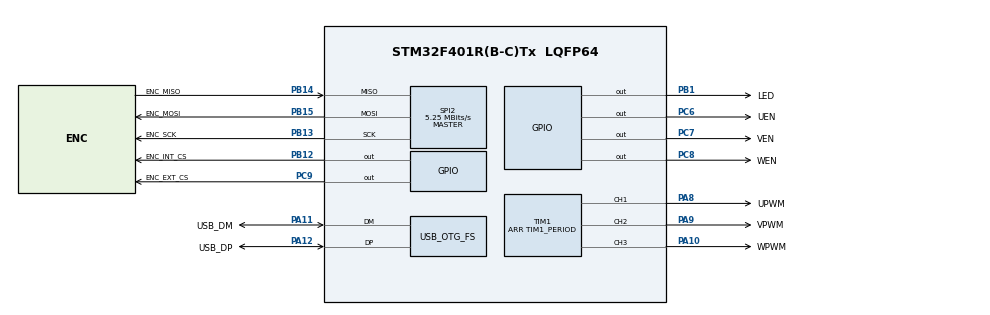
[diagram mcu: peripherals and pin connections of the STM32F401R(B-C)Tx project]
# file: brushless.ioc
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Mcu.Family=STM32F4
Mcu.Name=STM32F401R(B-C)Tx
Mcu.Package=LQFP64
NVIC.OTG_FS_IRQn=true\:2\:0\:true\:false\:true\:false\:true
NVIC.PriorityGroup=NVIC_PRIORITYGROUP_4
NVIC.SPI2_IRQn=true\:1\:0\:true\:false\:true\:true\:true
NVIC.TIM2_IRQn=true\:0\:0\:false\:false\:true\:true\:true
NVIC.TIM3_IRQn=true\:0\:0\:false\:false\:true\:true\:true
NVIC.TIM5_IRQn=true\:0\:0\:false\:false\:true\:true\:true
PA10.GPIO_Label=WPWM
PA10.Signal=S_TIM1_CH3
PA11.GPIO_Label=USB_DM
PA11.Mode=Device_Only
PA11.Signal=USB_OTG_FS_DM
PA12.GPIO_Label=USB_DP
PA12.Mode=Device_Only
PA12.Signal=USB_OTG_FS_DP
PA13.Mode=JTAG_4_pins
PA13.Signal=SYS_JTMS-SWDIO
PA14.Mode=JTAG_4_pins
PA14.Signal=SYS_JTCK-SWCLK
PA15.Mode=JTAG_4_pins
PA15.Signal=SYS_JTDI
PA8.GPIO_Label=UPWM
PA8.Signal=S_TIM1_CH1
PA9.GPIO_Label=VPWM
PA9.Signal=S_TIM1_CH2
PB1.GPIO_Label=LED
PB1.Signal=GPIO_Output
PB12.GPIO_Label=ENC_INT_CS
PB12.GPIO_Speed=GPIO_SPEED_FREQ_VERY_HIGH
PB12.PinState=GPIO_PIN_SET
PB12.Signal=GPIO_Output
PB13.GPIO_Label=ENC_SCK
PB13.Mode=Full_Duplex_Master
PB13.Signal=SPI2_SCK
PB14.GPIO_Label=ENC_MISO
PB14.Mode=Full_Duplex_Master
PB14.Signal=SPI2_MISO
PB15.GPIO_Label=ENC_MOSI
PB15.Mode=Full_Duplex_Master
PB15.Signal=SPI2_MOSI
PB3.Mode=JTAG_4_pins
PB3.Signal=SYS_JTDO-SWO
PC14-OSC32_IN.Mode=LSE-External-Oscillator
PC14-OSC32_IN.Signal=RCC_OSC32_IN
PC15-OSC32_OUT.Mode=LSE-External-Oscillator
PC15-OSC32_OUT.Signal=RCC_OSC32_OUT
PC6.GPIO_Label=UEN
PC6.Signal=GPIO_Output
PC7.GPIO_Label=VEN
PC7.Signal=GPIO_Output
PC8.GPIO_Label=WEN
PC8.Signal=GPIO_Output
PC9.GPIO_Label=ENC_EXT_CS
PC9.GPIO_Speed=GPIO_SPEED_FREQ_VERY_HIGH
PC9.PinState=GPIO_PIN_SET
PC9.Signal=GPIO_Output
PH0\ -\ OSC_IN.Mode=HSE-External-Oscillator
PH0\ -\ OSC_IN.Signal=RCC_OSC_IN
PH1\ -\ OSC_OUT.Mode=HSE-External-Oscillator
PH1\ -\ OSC_OUT.Signal=RCC_OSC_OUT
ProjectManager.HeapSize=0x200
ProjectManager.StackSize=0x400
ProjectManager.TargetToolchain=Makefile
RCC.48MHZClocksFreq_Value=48000000
RCC.AHBFreq_Value=84000000
RCC.APB1CLKDivider=RCC_HCLK_DIV2
RCC.APB1Freq_Value=42000000
RCC.APB1TimFreq_Value=84000000
RCC.APB2Freq_Value=84000000
RCC.APB2TimFreq_Value=84000000
RCC.CortexFreq_Value=84000000
RCC.HCLKFreq_Value=84000000
RCC.HSE_VALUE=8000000
RCC.HSI_VALUE=16000000
RCC.PLLM=4
RCC.PLLN=168
RCC.PLLP=RCC_PLLP_DIV4
RCC.PLLQ=7
RCC.RCC_RTC_Clock_Source=RCC_RTCCLKSOURCE_LSE
RCC.RCC_RTC_Clock_SourceVirtual=RCC_RTCCLKSOURCE_LSE
RCC.SYSCLKFreq_VALUE=84000000
RCC.SYSCLKSource=RCC_SYSCLKSOURCE_PLLCLK
RCC.VCOOutputFreq_Value=336000000
SH.S_TIM1_CH1.0=TIM1_CH1,PWM Generation1 CH1
SH.S_TIM1_CH2.0=TIM1_CH2,PWM Generation2 CH2
SH.S_TIM1_CH3.0=TIM1_CH3,PWM Generation3 CH3
SPI2.BaudRatePrescaler=SPI_BAUDRATEPRESCALER_8
SPI2.CLKPhase=SPI_PHASE_2EDGE
SPI2.CalculateBaudRate=5.25 MBits/s
SPI2.Direction=SPI_DIRECTION_2LINES
SPI2.Mode=SPI_MODE_MASTER
SPI2.VirtualType=VM_MASTER
TIM1.Channel-PWM\ Generation1\ CH1=TIM_CHANNEL_1
TIM1.Channel-PWM\ Generation2\ CH2=TIM_CHANNEL_2
TIM1.Channel-PWM\ Generation3\ CH3=TIM_CHANNEL_3
TIM1.CounterMode=TIM_COUNTERMODE_CENTERALIGNED3
TIM1.Period=TIM1_PERIOD
TIM1.Prescaler=TIM1_PRESCALAR
TIM1.TIM_MasterOutputTrigger=TIM_TRGO_RESET
TIM1.TIM_MasterSlaveMode=TIM_MASTERSLAVEMODE_DISABLE
TIM2.Period=TIM2_PERIOD
TIM2.Prescaler=TIM2_PRESCALAR
TIM2.TIM_MasterOutputTrigger=TIM_TRGO_RESET
TIM3.Channel-Output\ Compare1\ No\ Output=TIM_CHANNEL_1
TIM3.OCMode_1=TIM_OCMODE_TIMING
TIM3.Period=TIM3_PERIOD
TIM3.Prescaler=TIM3_PRESCALAR
TIM3.Pulse-Output\ Compare1\ No\ Output=ENC_SPI_DELAY
TIM3.TIM_MasterOutputTrigger=TIM_TRGO_RESET
TIM4.Period=TIM4_PERIOD
TIM4.Prescaler=TIM4_PRESCALAR
TIM4.TIM_MasterOutputTrigger=TIM_TRGO_UPDATE
TIM4.TIM_MasterSlaveMode=TIM_MASTERSLAVEMODE_ENABLE
TIM5.Channel-Output\ Compare1\ No\ Output=TIM_CHANNEL_1
TIM5.Period=TIM5_PERIOD
TIM5.Prescaler=TIM5_PRESCALAR
TIM5.Pulse-Output\ Compare1\ No\ Output=COMP_DELAY
USB_DEVICE.CLASS_NAME_FS=CDC
USB_DEVICE.MANUFACTURER_STRING=OpenHandicap
USB_DEVICE.PID_CDC_FS=0x4567
USB_DEVICE.PRODUCT_STRING_CDC_FS=Brushless Driver
USB_DEVICE.VID=0xF123
USB_DEVICE.VirtualMode=Cdc
USB_DEVICE.VirtualModeFS=Cdc_FS
USB_OTG_FS.VirtualMode=Device_Only
VP_TIM1_VS_ClockSourceINT.Mode=Internal
VP_TIM1_VS_ClockSourceITR.Mode=TriggerSource_ITR3
VP_TIM1_VS_ControllerModeReset.Mode=Reset Mode
VP_TIM2_VS_ClockSourceINT.Mode=Internal
VP_TIM2_VS_ClockSourceITR.Mode=TriggerSource_ITR3
VP_TIM2_VS_ControllerModeReset.Mode=Reset Mode
VP_TIM3_VS_ClockSourceINT.Mode=Internal
VP_TIM3_VS_ClockSourceITR.Mode=TriggerSource_ITR3
VP_TIM3_VS_ControllerModeReset.Mode=Reset Mode
VP_TIM3_VS_no_output1.Mode=Output Compare1 No Output
VP_TIM4_VS_ClockSourceINT.Mode=Internal
VP_TIM5_VS_ClockSourceINT.Mode=Internal
VP_TIM5_VS_no_output1.Mode=Output Compare1 No Output
VP_USB_DEVICE_VS_USB_DEVICE_CDC_FS.Mode=CDC_FS
board=custom

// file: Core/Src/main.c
/* USER CODE BEGIN Header */
/**
  ******************************************************************************
  * @file           : main.c
  * @brief          : Main program body
  ******************************************************************************
  * @attention
  *
  * <h2><center>&copy; Copyright (c) 2019 STMicroelectronics.
  * All rights reserved.</center></h2>
  * <h2><center>&copy; Copyright (c) 2019 Adrien Boussicault (USER CODE).
  * </center></h2>
  *
  * This software component is licensed by ST under BSD 3-Clause license,
  * the "License"; You may not use this file except in compliance with the
  * License. You may obtain a copy of the License at:
  *                        opensource.org/licenses/BSD-3-Clause
  *
  ******************************************************************************
  */
/* USER CODE END Header */

#include "main.h"
#include "usb_device.h"

/* USER CODE BEGIN Includes */
#include <terminal.h>
#include "debug.h"
#include "usbd_cdc_if.h"
#include <time.h>
#include <encoder.h>
#include <system.h>
#include <errors.h>
#include <frequence_definitions.h>

#define TIM1_PERIOD PWM_PERIOD
#define TIM2_PERIOD 2*PWM_PERIOD
#define TIM3_PERIOD 2*PWM_PERIOD*ENCODER_PERIOD
#define TIM4_PERIOD 4
#define TIM5_PERIOD 4294967295
#define TIM1_PRESCALAR 0
#define TIM2_PRESCALAR 0
#define TIM3_PRESCALAR 0
#define TIM4_PRESCALAR 0
#define TIM5_PRESCALAR 150 //5000
#define COMP_DELAY 1
/* USER CODE END Includes */

SPI_HandleTypeDef hspi2;

TIM_HandleTypeDef htim1;
TIM_HandleTypeDef htim2;
TIM_HandleTypeDef htim3;
TIM_HandleTypeDef htim4;
TIM_HandleTypeDef htim5;

void SystemClock_Config(void);
static void MX_GPIO_Init(void);
static void MX_SPI2_Init(void);
static void MX_TIM1_Init(void);
static void MX_TIM2_Init(void);
static void MX_TIM3_Init(void);
static void MX_TIM4_Init(void);
static void MX_TIM5_Init(void);

/* USER CODE BEGIN 0 */
TERMINAL_COMMAND(version, "firmware version")
{
  terminal_println(FIRMWARE_VERSION);
}

TERMINAL_COMMAND(led, "Set led")
{
  if(argc == 0){
    HAL_GPIO_TogglePin(LED_GPIO_Port, LED_Pin);
  }else if(argc == 1){
    if( atoi(argv[0])==1 ){
      HAL_GPIO_WritePin(LED_GPIO_Port, LED_Pin, GPIO_PIN_SET);
    }else{
      HAL_GPIO_WritePin(LED_GPIO_Port, LED_Pin, GPIO_PIN_RESET);
    }
  }else{
    terminal_println("Usage: led [1|0]");
  }
}

TERMINAL_COMMAND(test_us, "test micro oscillation on LED.")
{
  while(1){
    delay_us(1);
    HAL_GPIO_TogglePin(LED_GPIO_Port, LED_Pin);
  }
}

#ifdef DEBUG
TERMINAL_COMMAND(test_ms, "test milli oscillation on LED.")
{
  while(1){
    DELAY_MS(1);
    HAL_GPIO_TogglePin(LED_GPIO_Port, LED_Pin);
  }
}
#endif

TERMINAL_COMMAND(test_ns, "test milli oscillation on LED.")
{
  while(1){
    DELAY_AT_LEAST_NS(350);
    HAL_GPIO_TogglePin(LED_GPIO_Port, LED_Pin);
  }
}

void HAL_SPI_ErrorCallback(SPI_HandleTypeDef* hspi){
  if(hspi == &hspi2){
    encoder_error_spi_call_back();
  }
}

void HAL_SPI_TxRxCpltCallback(SPI_HandleTypeDef* hspi){
  if(hspi == &hspi2){
    encoder_spi_call_back();
  }
}

TERMINAL_PARAMETER_BOOL(st, "decl", false);

void start_and_synchronize_timers(){
  // We start timer 1, 2 and 4
  if( HAL_TIM_Base_Start(&htim1) != HAL_OK ){
    raise_error(ERROR_TIMER_INIT_AT_LINE, __LINE__);
  }
  if( HAL_TIM_Base_Start(&htim2) != HAL_OK ){
    raise_error(ERROR_TIMER_INIT_AT_LINE, __LINE__);
  }
  if( HAL_TIM_Base_Start(&htim3) != HAL_OK ){
    raise_error(ERROR_TIMER_INIT_AT_LINE, __LINE__);
  }

  //
  // Now, we will synchronize all timer by using the timer 4
  // Timer 4 is configured to send a trigger output (whose name is ITR3)
  // at each update.
  // Timer 1, 2, 3 are in slave mode, configured in reset mode and are waiting
  // for an input signal from TIM 4 (by using ITR3) to be reseted.
  //
  if( HAL_TIM_Base_Start(&htim4) != HAL_OK ){
     raise_error(ERROR_TIMER_INIT_AT_LINE, __LINE__);
  }
  delay_us(1); // We wait a little, to give time to TIM4 to be updated() (and
  //DELAY_MS(10000); // We wait a little, to give time to TIM4 to be updated() (and
                // ant trigger an output signal.
  if( HAL_TIM_Base_Stop(&htim4) != HAL_OK ){
    raise_error(ERROR_TIMER_INIT_AT_LINE, __LINE__);
  }

  // We can now start Output compare and interuption for timer 1, 2 and 3.
  if( HAL_TIM_OC_Start(&htim3, TIM_CHANNEL_1) != HAL_OK){
    raise_error(ERROR_TIMER_INIT_AT_LINE, __LINE__);
  };
  if( HAL_TIM_OC_Start_IT(&htim3, TIM_CHANNEL_1) != HAL_OK){
    raise_error(ERROR_TIMER_INIT_AT_LINE, __LINE__);
  };

  if( HAL_TIM_Base_Start_IT(&htim3) != HAL_OK ){
    raise_error(ERROR_TIMER_INIT_AT_LINE, __LINE__);
  }
  if( HAL_TIM_Base_Start_IT(&htim2) != HAL_OK ){
    raise_error(ERROR_TIMER_INIT_AT_LINE, __LINE__);
  };
  if( HAL_TIM_Base_Start_IT(&htim3) != HAL_OK ){
    raise_error(ERROR_TIMER_INIT_AT_LINE, __LINE__);
  }

    if( HAL_TIM_Base_Start(&htim5) != HAL_OK ){
      raise_error(ERROR_TIMER_INIT_AT_LINE, __LINE__);
    }
    if( HAL_TIM_OC_Start(&htim5, TIM_CHANNEL_1) != HAL_OK){
      raise_error(ERROR_TIMER_INIT_AT_LINE, __LINE__);
    };
    if( HAL_TIM_OC_Start_IT(&htim5, TIM_CHANNEL_1) != HAL_OK){
      raise_error(ERROR_TIMER_INIT_AT_LINE, __LINE__);
    };
}
/* USER CODE END 0 */

int main(void)
{

  /* MCU Configuration--------------------------------------------------------*/

  /* Reset of all peripherals, Initializes the Flash interface and the Systick. */
  HAL_Init();

  /* Configure the system clock */
  SystemClock_Config();

  /* Initialize all configured peripherals */
  MX_GPIO_Init();
  MX_SPI2_Init();
  MX_TIM1_Init();
  MX_TIM2_Init();
  MX_TIM3_Init();
  MX_TIM4_Init();
  MX_TIM5_Init();
  MX_USB_DEVICE_Init();
  /* USER CODE BEGIN 2 */

  get_serial()->init();
  terminal_init(get_serial());

  system_init();
  encoder_init(&hspi2, ENC_INT_CS_GPIO_Port,ENC_INT_CS_Pin);

  start_and_synchronize_timers();
  encoder_start();
  /* USER CODE END 2 */

  /* Infinite loop */
  /* USER CODE BEGIN WHILE */
  while (1)
  {
    system_tick();
#if 0
    COUNTDOWN(100){
      FREQ(frequence, 8);
      if( st ){
        HAL_GPIO_TogglePin(LED_GPIO_Port, LED_Pin);
        // HAL_GPIO_WritePin(LED_GPIO_Port, LED_Pin, GPIO_PIN_SET);
        start_read_encoder_position();
      }
      WATCHJ(true, 2000, "%.3f Khz", frequence/1000);
    }
#endif
    encoder_tick();
    get_serial()->tick();
    terminal_tick();

    /* USER CODE END WHILE */

  }
}

void SystemClock_Config(void)
{
  RCC_OscInitTypeDef RCC_OscInitStruct = {0};
  RCC_ClkInitTypeDef RCC_ClkInitStruct = {0};

  /** Configure the main internal regulator output voltage
  */
  __HAL_RCC_PWR_CLK_ENABLE();
  __HAL_PWR_VOLTAGESCALING_CONFIG(PWR_REGULATOR_VOLTAGE_SCALE2);
  /** Initializes the CPU, AHB and APB busses clocks
  */
  RCC_OscInitStruct.OscillatorType = RCC_OSCILLATORTYPE_HSE;
  RCC_OscInitStruct.HSEState = RCC_HSE_ON;
  RCC_OscInitStruct.PLL.PLLState = RCC_PLL_ON;
  RCC_OscInitStruct.PLL.PLLSource = RCC_PLLSOURCE_HSE;
  RCC_OscInitStruct.PLL.PLLM = CLK_PLLM;
  RCC_OscInitStruct.PLL.PLLN = CLK_PLLN;
  RCC_OscInitStruct.PLL.PLLP = RCC_PLLP_DIV4;
  _Static_assert( CLK_PLLP == RCC_PLLP_DIV4, "");
  RCC_OscInitStruct.PLL.PLLQ = 7;
  if (HAL_RCC_OscConfig(&RCC_OscInitStruct) != HAL_OK)
  {
    main_error_handler(__LINE__);
  }
  /** Initializes the CPU, AHB and APB busses clocks
  */
  RCC_ClkInitStruct.ClockType = RCC_CLOCKTYPE_HCLK|RCC_CLOCKTYPE_SYSCLK
                              |RCC_CLOCKTYPE_PCLK1|RCC_CLOCKTYPE_PCLK2;
  RCC_ClkInitStruct.SYSCLKSource = RCC_SYSCLKSOURCE_PLLCLK;
  RCC_ClkInitStruct.AHBCLKDivider = RCC_SYSCLK_DIV1;
  RCC_ClkInitStruct.APB1CLKDivider = RCC_HCLK_DIV2;
  RCC_ClkInitStruct.APB2CLKDivider = RCC_HCLK_DIV1;

  if (HAL_RCC_ClockConfig(&RCC_ClkInitStruct, FLASH_LATENCY_2) != HAL_OK)
  {
    main_error_handler(__LINE__);
  }
}

static void MX_SPI2_Init(void)
{

  /* SPI2 parameter configuration*/
  hspi2.Instance = SPI2;
  hspi2.Init.Mode = SPI_MODE_MASTER;
  hspi2.Init.Direction = SPI_DIRECTION_2LINES;
  hspi2.Init.DataSize = SPI_DATASIZE_8BIT;
  hspi2.Init.CLKPolarity = SPI_POLARITY_LOW;
  hspi2.Init.CLKPhase = SPI_PHASE_2EDGE;
  hspi2.Init.NSS = SPI_NSS_SOFT;
  hspi2.Init.BaudRatePrescaler = SPI_BAUDRATEPRESCALER_8;
  hspi2.Init.FirstBit = SPI_FIRSTBIT_MSB;
  hspi2.Init.TIMode = SPI_TIMODE_DISABLE;
  hspi2.Init.CRCCalculation = SPI_CRCCALCULATION_DISABLE;
  hspi2.Init.CRCPolynomial = 10;
  if (HAL_SPI_Init(&hspi2) != HAL_OK)
  {
    main_error_handler(__LINE__);
  }

}

static void MX_TIM1_Init(void)
{

  TIM_ClockConfigTypeDef sClockSourceConfig = {0};
  TIM_SlaveConfigTypeDef sSlaveConfig = {0};
  TIM_MasterConfigTypeDef sMasterConfig = {0};
  TIM_OC_InitTypeDef sConfigOC = {0};
  TIM_BreakDeadTimeConfigTypeDef sBreakDeadTimeConfig = {0};

  htim1.Instance = TIM1;
  htim1.Init.Prescaler = TIM1_PRESCALAR;
  htim1.Init.CounterMode = TIM_COUNTERMODE_CENTERALIGNED3;
  htim1.Init.Period = TIM1_PERIOD;
  htim1.Init.ClockDivision = TIM_CLOCKDIVISION_DIV1;
  htim1.Init.RepetitionCounter = 0;
  htim1.Init.AutoReloadPreload = TIM_AUTORELOAD_PRELOAD_DISABLE;
  if (HAL_TIM_Base_Init(&htim1) != HAL_OK)
  {
    main_error_handler(__LINE__);
  }
  sClockSourceConfig.ClockSource = TIM_CLOCKSOURCE_INTERNAL;
  if (HAL_TIM_ConfigClockSource(&htim1, &sClockSourceConfig) != HAL_OK)
  {
    main_error_handler(__LINE__);
  }
  if (HAL_TIM_PWM_Init(&htim1) != HAL_OK)
  {
    main_error_handler(__LINE__);
  }
  sSlaveConfig.SlaveMode = TIM_SLAVEMODE_RESET;
  sSlaveConfig.InputTrigger = TIM_TS_ITR3;
  if (HAL_TIM_SlaveConfigSynchro(&htim1, &sSlaveConfig) != HAL_OK)
  {
    main_error_handler(__LINE__);
  }
  sMasterConfig.MasterOutputTrigger = TIM_TRGO_RESET;
  sMasterConfig.MasterSlaveMode = TIM_MASTERSLAVEMODE_DISABLE;
  if (HAL_TIMEx_MasterConfigSynchronization(&htim1, &sMasterConfig) != HAL_OK)
  {
    main_error_handler(__LINE__);
  }
  sConfigOC.OCMode = TIM_OCMODE_PWM1;
  sConfigOC.Pulse = 0;
  sConfigOC.OCPolarity = TIM_OCPOLARITY_HIGH;
  sConfigOC.OCNPolarity = TIM_OCNPOLARITY_HIGH;
  sConfigOC.OCFastMode = TIM_OCFAST_DISABLE;
  sConfigOC.OCIdleState = TIM_OCIDLESTATE_RESET;
  sConfigOC.OCNIdleState = TIM_OCNIDLESTATE_RESET;
  if (HAL_TIM_PWM_ConfigChannel(&htim1, &sConfigOC, TIM_CHANNEL_1) != HAL_OK)
  {
    main_error_handler(__LINE__);
  }
  if (HAL_TIM_PWM_ConfigChannel(&htim1, &sConfigOC, TIM_CHANNEL_2) != HAL_OK)
  {
    main_error_handler(__LINE__);
  }
  if (HAL_TIM_PWM_ConfigChannel(&htim1, &sConfigOC, TIM_CHANNEL_3) != HAL_OK)
  {
    main_error_handler(__LINE__);
  }
  sBreakDeadTimeConfig.OffStateRunMode = TIM_OSSR_DISABLE;
  sBreakDeadTimeConfig.OffStateIDLEMode = TIM_OSSI_DISABLE;
  sBreakDeadTimeConfig.LockLevel = TIM_LOCKLEVEL_OFF;
  sBreakDeadTimeConfig.DeadTime = 0;
  sBreakDeadTimeConfig.BreakState = TIM_BREAK_DISABLE;
  sBreakDeadTimeConfig.BreakPolarity = TIM_BREAKPOLARITY_HIGH;
  sBreakDeadTimeConfig.AutomaticOutput = TIM_AUTOMATICOUTPUT_DISABLE;
  if (HAL_TIMEx_ConfigBreakDeadTime(&htim1, &sBreakDeadTimeConfig) != HAL_OK)
  {
    main_error_handler(__LINE__);
  }
  HAL_TIM_MspPostInit(&htim1);

}

static void MX_TIM2_Init(void)
{

  TIM_ClockConfigTypeDef sClockSourceConfig = {0};
  TIM_SlaveConfigTypeDef sSlaveConfig = {0};
  TIM_MasterConfigTypeDef sMasterConfig = {0};

  htim2.Instance = TIM2;
  htim2.Init.Prescaler = TIM2_PRESCALAR;
  htim2.Init.CounterMode = TIM_COUNTERMODE_UP;
  htim2.Init.Period = TIM2_PERIOD;
  htim2.Init.ClockDivision = TIM_CLOCKDIVISION_DIV1;
  htim2.Init.AutoReloadPreload = TIM_AUTORELOAD_PRELOAD_DISABLE;
  if (HAL_TIM_Base_Init(&htim2) != HAL_OK)
  {
    main_error_handler(__LINE__);
  }
  sClockSourceConfig.ClockSource = TIM_CLOCKSOURCE_INTERNAL;
  if (HAL_TIM_ConfigClockSource(&htim2, &sClockSourceConfig) != HAL_OK)
  {
    main_error_handler(__LINE__);
  }
  sSlaveConfig.SlaveMode = TIM_SLAVEMODE_RESET;
  sSlaveConfig.InputTrigger = TIM_TS_ITR3;
  if (HAL_TIM_SlaveConfigSynchro(&htim2, &sSlaveConfig) != HAL_OK)
  {
    main_error_handler(__LINE__);
  }
  sMasterConfig.MasterOutputTrigger = TIM_TRGO_RESET;
  sMasterConfig.MasterSlaveMode = TIM_MASTERSLAVEMODE_DISABLE;
  if (HAL_TIMEx_MasterConfigSynchronization(&htim2, &sMasterConfig) != HAL_OK)
  {
    main_error_handler(__LINE__);
  }

}

static void MX_TIM3_Init(void)
{

  TIM_ClockConfigTypeDef sClockSourceConfig = {0};
  TIM_SlaveConfigTypeDef sSlaveConfig = {0};
  TIM_MasterConfigTypeDef sMasterConfig = {0};
  TIM_OC_InitTypeDef sConfigOC = {0};

  htim3.Instance = TIM3;
  htim3.Init.Prescaler = TIM3_PRESCALAR;
  htim3.Init.CounterMode = TIM_COUNTERMODE_UP;
  htim3.Init.Period = TIM3_PERIOD;
  htim3.Init.ClockDivision = TIM_CLOCKDIVISION_DIV1;
  htim3.Init.AutoReloadPreload = TIM_AUTORELOAD_PRELOAD_DISABLE;
  if (HAL_TIM_Base_Init(&htim3) != HAL_OK)
  {
    main_error_handler(__LINE__);
  }
  sClockSourceConfig.ClockSource = TIM_CLOCKSOURCE_INTERNAL;
  if (HAL_TIM_ConfigClockSource(&htim3, &sClockSourceConfig) != HAL_OK)
  {
    main_error_handler(__LINE__);
  }
  if (HAL_TIM_OC_Init(&htim3) != HAL_OK)
  {
    main_error_handler(__LINE__);
  }
  sSlaveConfig.SlaveMode = TIM_SLAVEMODE_RESET;
  sSlaveConfig.InputTrigger = TIM_TS_ITR3;
  if (HAL_TIM_SlaveConfigSynchro(&htim3, &sSlaveConfig) != HAL_OK)
  {
    main_error_handler(__LINE__);
  }
  sMasterConfig.MasterOutputTrigger = TIM_TRGO_RESET;
  sMasterConfig.MasterSlaveMode = TIM_MASTERSLAVEMODE_DISABLE;
  if (HAL_TIMEx_MasterConfigSynchronization(&htim3, &sMasterConfig) != HAL_OK)
  {
    main_error_handler(__LINE__);
  }
  sConfigOC.OCMode = TIM_OCMODE_TIMING;
  sConfigOC.Pulse = ENC_SPI_DELAY;
  sConfigOC.OCPolarity = TIM_OCPOLARITY_HIGH;
  sConfigOC.OCFastMode = TIM_OCFAST_DISABLE;
  if (HAL_TIM_OC_ConfigChannel(&htim3, &sConfigOC, TIM_CHANNEL_1) != HAL_OK)
  {
    main_error_handler(__LINE__);
  }

}

static void MX_TIM4_Init(void)
{

  TIM_ClockConfigTypeDef sClockSourceConfig = {0};
  TIM_MasterConfigTypeDef sMasterConfig = {0};

  htim4.Instance = TIM4;
  htim4.Init.Prescaler = TIM4_PRESCALAR;
  htim4.Init.CounterMode = TIM_COUNTERMODE_UP;
  htim4.Init.Period = TIM4_PERIOD;
  htim4.Init.ClockDivision = TIM_CLOCKDIVISION_DIV1;
  htim4.Init.AutoReloadPreload = TIM_AUTORELOAD_PRELOAD_DISABLE;
  if (HAL_TIM_Base_Init(&htim4) != HAL_OK)
  {
    main_error_handler(__LINE__);
  }
  sClockSourceConfig.ClockSource = TIM_CLOCKSOURCE_INTERNAL;
  if (HAL_TIM_ConfigClockSource(&htim4, &sClockSourceConfig) != HAL_OK)
  {
    main_error_handler(__LINE__);
  }
  sMasterConfig.MasterOutputTrigger = TIM_TRGO_UPDATE;
  sMasterConfig.MasterSlaveMode = TIM_MASTERSLAVEMODE_ENABLE;
  if (HAL_TIMEx_MasterConfigSynchronization(&htim4, &sMasterConfig) != HAL_OK)
  {
    main_error_handler(__LINE__);
  }

}

static void MX_TIM5_Init(void)
{

  TIM_ClockConfigTypeDef sClockSourceConfig = {0};
  TIM_MasterConfigTypeDef sMasterConfig = {0};
  TIM_OC_InitTypeDef sConfigOC = {0};

  htim5.Instance = TIM5;
  htim5.Init.Prescaler = TIM5_PRESCALAR;
  htim5.Init.CounterMode = TIM_COUNTERMODE_UP;
  htim5.Init.Period = TIM5_PERIOD;
  htim5.Init.ClockDivision = TIM_CLOCKDIVISION_DIV1;
  htim5.Init.AutoReloadPreload = TIM_AUTORELOAD_PRELOAD_DISABLE;
  if (HAL_TIM_Base_Init(&htim5) != HAL_OK)
  {
    main_error_handler(__LINE__);
  }
  sClockSourceConfig.ClockSource = TIM_CLOCKSOURCE_INTERNAL;
  if (HAL_TIM_ConfigClockSource(&htim5, &sClockSourceConfig) != HAL_OK)
  {
    main_error_handler(__LINE__);
  }
  if (HAL_TIM_OC_Init(&htim5) != HAL_OK)
  {
    main_error_handler(__LINE__);
  }
  sMasterConfig.MasterOutputTrigger = TIM_TRGO_RESET;
  sMasterConfig.MasterSlaveMode = TIM_MASTERSLAVEMODE_DISABLE;
  if (HAL_TIMEx_MasterConfigSynchronization(&htim5, &sMasterConfig) != HAL_OK)
  {
    main_error_handler(__LINE__);
  }
  sConfigOC.OCMode = TIM_OCMODE_TIMING;
  sConfigOC.Pulse = COMP_DELAY;
  sConfigOC.OCPolarity = TIM_OCPOLARITY_HIGH;
  sConfigOC.OCFastMode = TIM_OCFAST_DISABLE;
  if (HAL_TIM_OC_ConfigChannel(&htim5, &sConfigOC, TIM_CHANNEL_1) != HAL_OK)
  {
    main_error_handler(__LINE__);
  }

}

static void MX_GPIO_Init(void)
{
  GPIO_InitTypeDef GPIO_InitStruct = {0};

  /* GPIO Ports Clock Enable */
  __HAL_RCC_GPIOC_CLK_ENABLE();
  __HAL_RCC_GPIOH_CLK_ENABLE();
  __HAL_RCC_GPIOB_CLK_ENABLE();
  __HAL_RCC_GPIOA_CLK_ENABLE();

  /*Configure GPIO pin Output Level */
  HAL_GPIO_WritePin(LED_GPIO_Port, LED_Pin, GPIO_PIN_RESET);

  /*Configure GPIO pin Output Level */
  HAL_GPIO_WritePin(ENC_INT_CS_GPIO_Port, ENC_INT_CS_Pin, GPIO_PIN_SET);

  /*Configure GPIO pin Output Level */
  HAL_GPIO_WritePin(GPIOC, UEN_Pin|VEN_Pin|WEN_Pin, GPIO_PIN_RESET);

  /*Configure GPIO pin Output Level */
  HAL_GPIO_WritePin(ENC_EXT_CS_GPIO_Port, ENC_EXT_CS_Pin, GPIO_PIN_SET);

  /*Configure GPIO pin : LED_Pin */
  GPIO_InitStruct.Pin = LED_Pin;
  GPIO_InitStruct.Mode = GPIO_MODE_OUTPUT_PP;
  GPIO_InitStruct.Pull = GPIO_NOPULL;
  GPIO_InitStruct.Speed = GPIO_SPEED_FREQ_LOW;
  HAL_GPIO_Init(LED_GPIO_Port, &GPIO_InitStruct);

  /*Configure GPIO pin : ENC_INT_CS_Pin */
  GPIO_InitStruct.Pin = ENC_INT_CS_Pin;
  GPIO_InitStruct.Mode = GPIO_MODE_OUTPUT_PP;
  GPIO_InitStruct.Pull = GPIO_NOPULL;
  GPIO_InitStruct.Speed = GPIO_SPEED_FREQ_VERY_HIGH;
  HAL_GPIO_Init(ENC_INT_CS_GPIO_Port, &GPIO_InitStruct);

  /*Configure GPIO pins : UEN_Pin VEN_Pin WEN_Pin */
  GPIO_InitStruct.Pin = UEN_Pin|VEN_Pin|WEN_Pin;
  GPIO_InitStruct.Mode = GPIO_MODE_OUTPUT_PP;
  GPIO_InitStruct.Pull = GPIO_NOPULL;
  GPIO_InitStruct.Speed = GPIO_SPEED_FREQ_LOW;
  HAL_GPIO_Init(GPIOC, &GPIO_InitStruct);

  /*Configure GPIO pin : ENC_EXT_CS_Pin */
  GPIO_InitStruct.Pin = ENC_EXT_CS_Pin;
  GPIO_InitStruct.Mode = GPIO_MODE_OUTPUT_PP;
  GPIO_InitStruct.Pull = GPIO_NOPULL;
  GPIO_InitStruct.Speed = GPIO_SPEED_FREQ_VERY_HIGH;
  HAL_GPIO_Init(ENC_EXT_CS_GPIO_Port, &GPIO_InitStruct);

}

void main_error_handler(uint32_t value)
{
  /* USER CODE BEGIN main_error_handler_Debug */
  raise_error(ERROR_STM32_HAL_LIBRARY, value);
  /* USER CODE END main_error_handler_Debug */
}

#ifdef  USE_FULL_ASSERT
/**
  * @brief  Reports the name of the source file and the source line number
  *         where the assert_param error has occurred.
  * @param  file: pointer to the source file name
  * @param  line: assert_param error line source number
  * @retval None
  */
void assert_failed(uint8_t *file, uint32_t line)
{
  /* USER CODE BEGIN 6 */
  raise_error(ERROR_ASSERTION, line);
  raise_error(ERROR_STRING, (uint32_t) file);
  /* USER CODE END 6 */
}
#endif /* USE_FULL_ASSERT */

/************************ (C) COPYRIGHT STMicroelectronics *****END OF FILE****/
